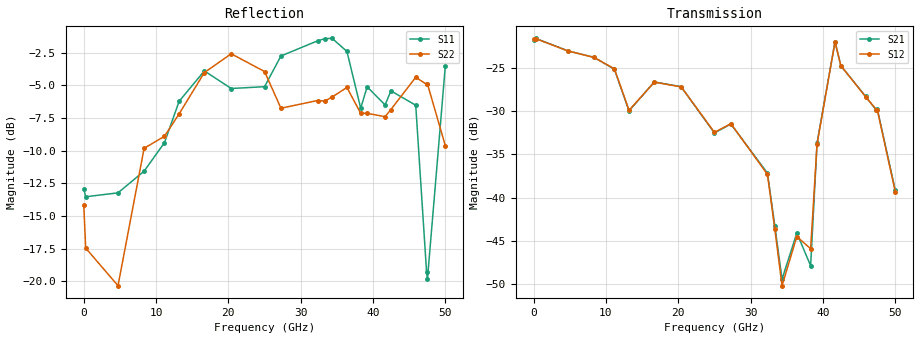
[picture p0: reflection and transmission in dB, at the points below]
!Keysight Technologies,N5245B,MY58422270,A.16.20.02
!Date: Thursday, March 05, 2026 01:25:37
!Correction: S11(C  2-Port  )
!S21(C  2-Port  )
!S12(C  2-Port  )
!S22(C  2-Port  )
!S2P File: Measurements: S11, S21, S12, S22:
# Hz S  dB  R 50
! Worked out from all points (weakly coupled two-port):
!   3201 points, 10 MHz to 50 GHz, reference 50 ohm
!   highest |S21| = -21.54 dB at 275.6 MHz (marker M1); lowest = -49.4 dB at 34.35 GHz (marker M2)
!   lowest |S11| = -19.8 dB at 47.53 GHz (marker M3), VSWR 1.23, Z = 46 + j8.98 ohm
!   |S11| at or under -10 dB: start of sweep to 10.1 GHz; 11.36 GHz to 11.92 GHz (560.5 MHz wide, 4.82 % of centre); 46.67 GHz to 48.28 GHz (1.613 GHz wide, 3.4 % of centre)
!   |S22| runs from -20.4 to -2.5 dB; largest |S21 - S12| = 0.0092
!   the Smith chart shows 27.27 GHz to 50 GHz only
!   S11 on the Smith chart (normalised r, x): 27.27 GHz: 0.18, +0.37; 32.33 GHz: 0.42, +1.88; 36.39 GHz: 2.32, -3.29; 42.47 GHz: 0.99, -1.26; 47.41 GHz: 0.84, +0.13; 50 GHz: 0.61, -1.35
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1e7  -12.91 -4.5  -21.70 3.9  -21.61 4.6  -14.19 34.5
2.755719e8  -13.53 -12.0  -21.54 -11.1  -21.57 -10.9  -17.46 -12.1
4.743428e9  -13.23 -118.8  -22.99 176.2  -23.00 176.2  -20.34 -122.3
8.352081e9  -11.57 174.9  -23.74 26.5  -23.75 26.5  -9.82 -161.5
1.116402e10  -9.39 106.4  -25.11 -82.6  -25.07 -82.7  -8.90 89.3
1.319486e10  -6.22 63.2  -29.95 -141.0  -29.88 -141.1  -7.18 -20.4
1.667854e10  -3.89 -43.8  -26.59 157.6  -26.62 157.5  -4.02 -139.6
2.039655e10  -5.24 -121.5  -27.15 40.1  -27.16 40.2  -2.58 155.4
2.5005e10  -5.10 179.9  -32.51 -64.4  -32.44 -64.4  -3.94 71.3
2.727017e10  -2.75 138.0  -31.47 -115.0  -31.43 -113.6  -6.75 30.7
3.233166e10  -1.59 54.2  -37.16 47.1  -37.31 46.3  -6.16 -104.2
3.334708e10  -1.42 36.1  -43.26 4.6  -43.65 0.5  -6.20 -126.4
3.434688e10  -1.40 18.3  -49.45 -82.3  -50.21 -99.6  -5.89 -147.3
3.639335e10  -2.40 -23.4  -44.10 114.1  -44.51 112.7  -5.16 173.8
3.829922e10  -6.75 -22.2  -47.90 91.8  -45.93 -83.4  -7.14 138.9
3.918966e10  -5.11 -32.4  -33.67 93.3  -33.77 94.8  -7.14 137.6
4.167354e10  -6.50 -52.5  -21.92 -58.0  -21.95 -58.3  -7.40 117.4
4.247026e10  -5.42 -58.0  -24.70 -120.0  -24.70 -120.0  -6.85 113.0
4.590707e10  -6.52 -117.6  -28.27 54.3  -28.32 54.1  -4.38 62.9
4.740677e10  -19.29 137.5  -29.89 -2.7  -29.82 -2.1  -4.92 42.9
4.753174e10  -19.81 108.8  -29.77 -5.0  -29.90 -5.0  -4.90 41.4
5e10  -3.50 -66.1  -39.13 -139.4  -39.30 -133.5  -9.62 2.6
